#  --========================================================================--
#  This confidential and proprietary software may be used only as
#  authorised by a licensing agreement from ARM Limited
#    (C) COPYRIGHT 2005 ARM Limited
#        ALL RIGHTS RESERVED
#  The entire notice above must be reproduced on all authorised
#  copies and copies may only be made to the extent permitted
#  by a licensing agreement from ARM Limited.
#
#  ----------------------------------------------------------------------------
# 
# LEF OUT API 
# User Name : user 
# Date : Tue Mar  8 17:30:10 2005
# 
VERSION 5.3 ;
NAMESCASESENSITIVE ON ;
BUSBITCHARS "[]" ;
DIVIDERCHAR "/" ;

SITE ARM7TDMI_site
 CLASS core ;
 SIZE 914.85 BY 584.15 ;
END ARM7TDMI_site


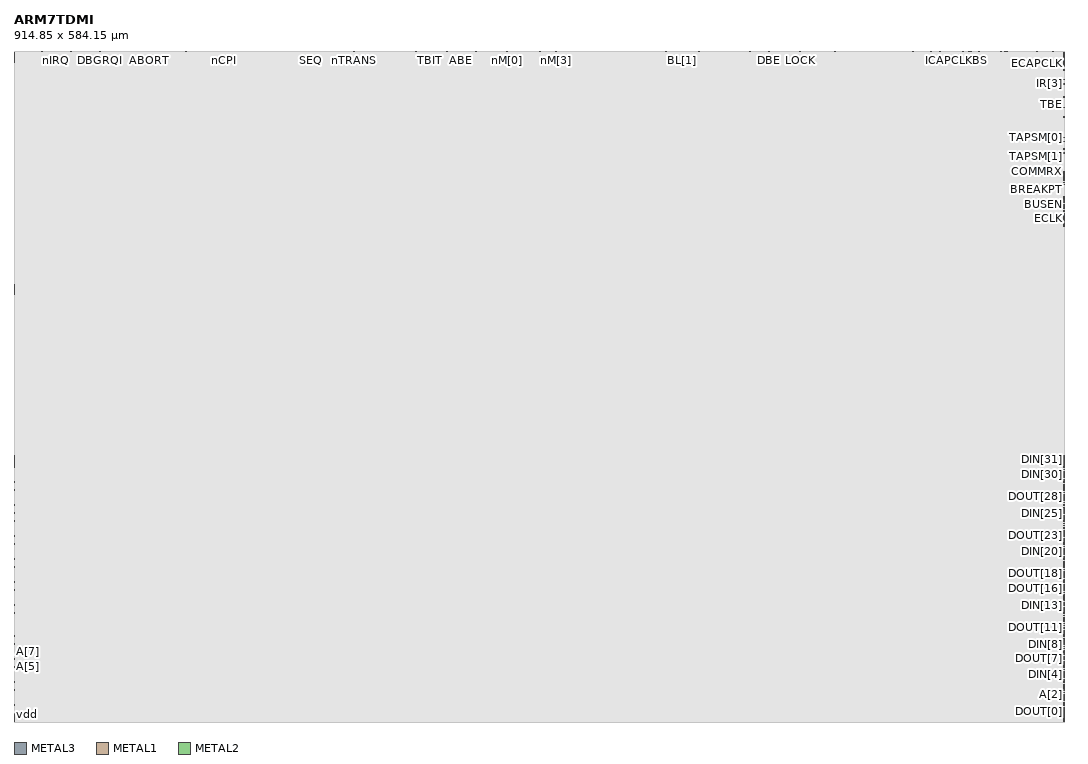
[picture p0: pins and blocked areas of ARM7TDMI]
MACRO ARM7TDMI
 CLASS BLOCK ;
 ORIGIN 0 0 ;
 FOREIGN ARM7TDMI 0.00 0.00 ;
 SYMMETRY X Y R90 ;
 SIZE 914.85 BY 584.15 ;
SITE ARM7TDMI_site ;

 PIN DOUT[25]
 DIRECTION OUTPUT ;
 USE SIGNAL ;
 PORT
 LAYER METAL3 ;
 RECT 914.48 175.98 914.85 176.54 ;
 END
 END DOUT[25]

 PIN A[25]
 DIRECTION OUTPUT ;
 USE SIGNAL ;
 PORT
 LAYER METAL3 ;
 RECT 914.48 177.52 914.85 178.08 ;
 END
 PORT
 LAYER METAL3 ;
 RECT 0 181.82 0.37 182.38 ;
 END
 ANTENNASIZE 0.324 ;
 END A[25]

 PIN D[25]
 DIRECTION INOUT ;
 USE SIGNAL ;
 PORT
 LAYER METAL3 ;
 RECT 914.48 179.48 914.85 180.04 ;
 END
 ANTENNASIZE 2.394 ;
 END D[25]

 PIN DIN[24]
 DIRECTION INPUT ;
 USE SIGNAL ;
 PORT
 LAYER METAL3 ;
 RECT 914.48 174.88 914.85 175.44 ;
 END
 ANTENNASIZE 1.08 ;
 END DIN[24]

 PIN DOUT[24]
 DIRECTION OUTPUT ;
 USE SIGNAL ;
 PORT
 LAYER METAL3 ;
 RECT 914.48 169.28 914.85 169.84 ;
 END
 END DOUT[24]

 PIN A[24]
 DIRECTION OUTPUT ;
 USE SIGNAL ;
 PORT
 LAYER METAL3 ;
 RECT 914.48 170.82 914.85 171.38 ;
 END
 PORT
 LAYER METAL3 ;
 RECT 0 175.12 0.37 175.68 ;
 END
 ANTENNASIZE 0.324 ;
 END A[24]

 PIN D[24]
 DIRECTION INOUT ;
 USE SIGNAL ;
 PORT
 LAYER METAL3 ;
 RECT 914.48 172.78 914.85 173.34 ;
 END
 ANTENNASIZE 2.394 ;
 END D[24]

 PIN DIN[23]
 DIRECTION INPUT ;
 USE SIGNAL ;
 PORT
 LAYER METAL3 ;
 RECT 914.48 168.18 914.85 168.74 ;
 END
 ANTENNASIZE 1.08 ;
 END DIN[23]

 PIN DOUT[23]
 DIRECTION OUTPUT ;
 USE SIGNAL ;
 PORT
 LAYER METAL3 ;
 RECT 914.48 162.58 914.85 163.14 ;
 END
 END DOUT[23]

 PIN A[23]
 DIRECTION OUTPUT ;
 USE SIGNAL ;
 PORT
 LAYER METAL3 ;
 RECT 914.48 164.12 914.85 164.68 ;
 END
 PORT
 LAYER METAL3 ;
 RECT 0 168.42 0.37 168.98 ;
 END
 ANTENNASIZE 0.324 ;
 END A[23]

 PIN D[23]
 DIRECTION INOUT ;
 USE SIGNAL ;
 PORT
 LAYER METAL3 ;
 RECT 914.48 166.08 914.85 166.64 ;
 END
 ANTENNASIZE 2.07 ;
 END D[23]

 PIN DIN[22]
 DIRECTION INPUT ;
 USE SIGNAL ;
 PORT
 LAYER METAL3 ;
 RECT 914.48 161.48 914.85 162.04 ;
 END
 ANTENNASIZE 1.08 ;
 END DIN[22]

 PIN DOUT[22]
 DIRECTION OUTPUT ;
 USE SIGNAL ;
 PORT
 LAYER METAL3 ;
 RECT 914.48 155.88 914.85 156.44 ;
 END
 END DOUT[22]

 PIN A[22]
 DIRECTION OUTPUT ;
 USE SIGNAL ;
 PORT
 LAYER METAL3 ;
 RECT 914.48 157.42 914.85 157.98 ;
 END
 PORT
 LAYER METAL3 ;
 RECT 0 161.72 0.37 162.28 ;
 END
 ANTENNASIZE 0.324 ;
 END A[22]

 PIN D[22]
 DIRECTION INOUT ;
 USE SIGNAL ;
 PORT
 LAYER METAL3 ;
 RECT 914.48 159.38 914.85 159.94 ;
 END
 ANTENNASIZE 2.07 ;
 END D[22]

 PIN DIN[21]
 DIRECTION INPUT ;
 USE SIGNAL ;
 PORT
 LAYER METAL3 ;
 RECT 914.48 154.78 914.85 155.34 ;
 END
 ANTENNASIZE 1.08 ;
 END DIN[21]

 PIN DOUT[21]
 DIRECTION OUTPUT ;
 USE SIGNAL ;
 PORT
 LAYER METAL3 ;
 RECT 914.48 149.18 914.85 149.74 ;
 END
 END DOUT[21]

 PIN A[21]
 DIRECTION OUTPUT ;
 USE SIGNAL ;
 PORT
 LAYER METAL3 ;
 RECT 914.48 150.72 914.85 151.28 ;
 END
 PORT
 LAYER METAL3 ;
 RECT 0 155.02 0.37 155.58 ;
 END
 ANTENNASIZE 0.324 ;
 END A[21]

 PIN D[21]
 DIRECTION INOUT ;
 USE SIGNAL ;
 PORT
 LAYER METAL3 ;
 RECT 914.48 152.68 914.85 153.24 ;
 END
 ANTENNASIZE 2.07 ;
 END D[21]

 PIN DIN[20]
 DIRECTION INPUT ;
 USE SIGNAL ;
 PORT
 LAYER METAL3 ;
 RECT 914.48 148.08 914.85 148.64 ;
 END
 ANTENNASIZE 1.08 ;
 END DIN[20]

 PIN DOUT[20]
 DIRECTION OUTPUT ;
 USE SIGNAL ;
 PORT
 LAYER METAL3 ;
 RECT 914.48 142.48 914.85 143.04 ;
 END
 END DOUT[20]

 PIN A[20]
 DIRECTION OUTPUT ;
 USE SIGNAL ;
 PORT
 LAYER METAL3 ;
 RECT 914.48 144.02 914.85 144.58 ;
 END
 PORT
 LAYER METAL3 ;
 RECT 0 148.32 0.37 148.88 ;
 END
 ANTENNASIZE 0.324 ;
 END A[20]

 PIN D[20]
 DIRECTION INOUT ;
 USE SIGNAL ;
 PORT
 LAYER METAL3 ;
 RECT 914.48 145.98 914.85 146.54 ;
 END
 ANTENNASIZE 2.394 ;
 END D[20]

 PIN DIN[19]
 DIRECTION INPUT ;
 USE SIGNAL ;
 PORT
 LAYER METAL3 ;
 RECT 914.48 141.38 914.85 141.94 ;
 END
 ANTENNASIZE 1.08 ;
 END DIN[19]

 PIN DOUT[18]
 DIRECTION OUTPUT ;
 USE SIGNAL ;
 PORT
 LAYER METAL3 ;
 RECT 914.48 129.08 914.85 129.64 ;
 END
 END DOUT[18]

 PIN ECLK
 DIRECTION OUTPUT ;
 USE SIGNAL ;
 PORT
 LAYER METAL3 ;
 RECT 914.48 445.12 914.85 445.68 ;
 END
 ANTENNASIZE 6.093 ;
 END ECLK

 PIN MCLK
 DIRECTION INPUT ;
 USE SIGNAL ;
 PORT
 LAYER METAL3 ;
 RECT 914.48 441.9 914.85 442.46 ;
 END
 ANTENNASIZE 4.05 ;
 END MCLK

 PIN RSTCLKBS
 DIRECTION OUTPUT ;
 USE SIGNAL ;
 PORT
 LAYER METAL3 ;
 RECT 914.48 442.74 914.85 443.3 ;
 END
 ANTENNASIZE 2.025 ;
 END RSTCLKBS

 PIN vdd
 DIRECTION INOUT ;
 USE POWER ;
 PORT
 LAYER METAL3 ;
 RECT 0 227.8 0.28 231.8 ;
 END
 PORT
 LAYER METAL3 ;
 RECT 914.57 227.8 914.85 231.8 ;
 END
 PORT
 LAYER METAL3 ;
 RECT 0 376.91 0.28 380.89 ;
 END
 PORT
 LAYER METAL3 ;
 RECT 914.57 437 914.85 441 ;
 END
 PORT
 LAYER METAL3 ;
 RECT 914.57 574.96 914.85 578.96 ;
 END
 PORT
 LAYER METAL3 ;
 RECT 0 574.97 0.28 578.95 ;
 END
 PORT
 LAYER METAL1 ;
 RECT 0 0.6 0.28 6.54 ;
 END
 PORT
 LAYER METAL1 ;
 RECT 914.57 0.6 914.85 6.54 ;
 END
 END vdd

 PIN nTRST
 DIRECTION INPUT ;
 USE SIGNAL ;
 PORT
 LAYER METAL3 ;
 RECT 914.48 559.42 914.85 559.98 ;
 END
 ANTENNASIZE 0.99 ;
 END nTRST

 PIN RANGEOUT1
 DIRECTION OUTPUT ;
 USE SIGNAL ;
 PORT
 LAYER METAL3 ;
 RECT 914.48 447.52 914.85 448.08 ;
 END
 END RANGEOUT1

 PIN RANGEOUT0
 DIRECTION OUTPUT ;
 USE SIGNAL ;
 PORT
 LAYER METAL3 ;
 RECT 914.48 449.12 914.85 449.68 ;
 END
 END RANGEOUT0

 PIN BUSEN
 DIRECTION INPUT ;
 USE SIGNAL ;
 PORT
 LAYER METAL3 ;
 RECT 914.48 450.72 914.85 451.28 ;
 END
 ANTENNASIZE 0.522 ;
 END BUSEN

 PIN EXTERN0
 DIRECTION INPUT ;
 USE SIGNAL ;
 PORT
 LAYER METAL3 ;
 RECT 914.48 452.32 914.85 452.88 ;
 END
 ANTENNASIZE 0.522 ;
 END EXTERN0

 PIN DBGACK
 DIRECTION OUTPUT ;
 USE SIGNAL ;
 PORT
 LAYER METAL3 ;
 RECT 914.48 453.92 914.85 454.48 ;
 END
 END DBGACK

 PIN EXTERN1
 DIRECTION INPUT ;
 USE SIGNAL ;
 PORT
 LAYER METAL3 ;
 RECT 914.48 455.52 914.85 456.08 ;
 END
 ANTENNASIZE 0.522 ;
 END EXTERN1

 PIN BREAKPT
 DIRECTION INPUT ;
 USE SIGNAL ;
 PORT
 LAYER METAL3 ;
 RECT 914.48 457.12 914.85 457.68 ;
 END
 ANTENNASIZE 0.522 ;
 END BREAKPT

 PIN CPB
 DIRECTION INPUT ;
 USE SIGNAL ;
 PORT
 LAYER METAL3 ;
 RECT 914.48 469.78 914.85 470.34 ;
 END
 ANTENNASIZE 0.522 ;
 END CPB

 PIN CPA
 DIRECTION INPUT ;
 USE SIGNAL ;
 PORT
 LAYER METAL3 ;
 RECT 914.48 471.38 914.85 471.94 ;
 END
 ANTENNASIZE 0.522 ;
 END CPA

 PIN nENOUTI
 DIRECTION OUTPUT ;
 USE SIGNAL ;
 PORT
 LAYER METAL3 ;
 RECT 914.48 472.98 914.85 473.54 ;
 END
 END nENOUTI

 PIN DBGEN
 DIRECTION INPUT ;
 USE SIGNAL ;
 PORT
 LAYER METAL3 ;
 RECT 914.48 474.58 914.85 475.14 ;
 END
 ANTENNASIZE 0.522 ;
 END DBGEN

 PIN COMMTX
 DIRECTION OUTPUT ;
 USE SIGNAL ;
 PORT
 LAYER METAL3 ;
 RECT 914.48 476.18 914.85 476.74 ;
 END
 END COMMTX

 PIN DBGRQ
 DIRECTION INPUT ;
 USE SIGNAL ;
 PORT
 LAYER METAL3 ;
 RECT 914.48 477.78 914.85 478.34 ;
 END
 ANTENNASIZE 0.522 ;
 END DBGRQ

 PIN COMMRX
 DIRECTION OUTPUT ;
 USE SIGNAL ;
 PORT
 LAYER METAL3 ;
 RECT 914.48 479.38 914.85 479.94 ;
 END
 END COMMRX

 PIN SDINBS
 DIRECTION OUTPUT ;
 USE SIGNAL ;
 PORT
 LAYER METAL3 ;
 RECT 914.48 468.18 914.85 468.74 ;
 END
 ANTENNASIZE 0.558 ;
 END SDINBS

 PIN TAPSM[3]
 DIRECTION OUTPUT ;
 USE SIGNAL ;
 PORT
 LAYER METAL3 ;
 RECT 914.48 495.52 914.85 496.08 ;
 END
 END TAPSM[3]

 PIN TAPSM[1]
 DIRECTION OUTPUT ;
 USE SIGNAL ;
 PORT
 LAYER METAL3 ;
 RECT 914.48 499.12 914.85 499.68 ;
 END
 END TAPSM[1]

 PIN TAPSM[2]
 DIRECTION OUTPUT ;
 USE SIGNAL ;
 PORT
 LAYER METAL3 ;
 RECT 914.48 505.42 914.85 505.98 ;
 END
 END TAPSM[2]

 PIN TAPSM[0]
 DIRECTION OUTPUT ;
 USE SIGNAL ;
 PORT
 LAYER METAL3 ;
 RECT 914.48 509.02 914.85 509.58 ;
 END
 END TAPSM[0]

 PIN HIGHZ
 DIRECTION OUTPUT ;
 USE SIGNAL ;
 PORT
 LAYER METAL3 ;
 RECT 914.48 527.02 914.85 527.58 ;
 END
 END HIGHZ

 PIN nHIGHZ
 DIRECTION OUTPUT ;
 USE SIGNAL ;
 PORT
 LAYER METAL3 ;
 RECT 914.48 535.12 914.85 535.68 ;
 END
 END nHIGHZ

 PIN TBE
 DIRECTION INPUT ;
 USE SIGNAL ;
 PORT
 LAYER METAL3 ;
 RECT 914.48 544.12 914.85 544.68 ;
 END
 ANTENNASIZE 0.468 ;
 END TBE

 PIN IR[3]
 DIRECTION OUTPUT ;
 USE SIGNAL ;
 PORT
 LAYER METAL3 ;
 RECT 914.48 555.82 914.85 556.38 ;
 END
 END IR[3]

 PIN IR[1]
 DIRECTION OUTPUT ;
 USE SIGNAL ;
 PORT
 LAYER METAL3 ;
 RECT 914.48 567.52 914.85 568.08 ;
 END
 END IR[1]

 PIN IR[0]
 DIRECTION OUTPUT ;
 USE SIGNAL ;
 PORT
 LAYER METAL3 ;
 RECT 914.48 572.92 914.85 573.48 ;
 END
 END IR[0]

 PIN IR[2]
 DIRECTION OUTPUT ;
 USE SIGNAL ;
 PORT
 LAYER METAL3 ;
 RECT 914.48 571.12 914.85 571.68 ;
 END
 END IR[2]

 PIN ECAPCLK
 DIRECTION OUTPUT ;
 USE SIGNAL ;
 PORT
 LAYER METAL3 ;
 RECT 914.48 573.82 914.85 574.38 ;
 END
 END ECAPCLK

 PIN vss
 DIRECTION INOUT ;
 USE GROUND ;
 PORT
 LAYER METAL3 ;
 RECT 0 1.7 0.28 7.7 ;
 END
 PORT
 LAYER METAL3 ;
 RECT 914.57 1.7 914.85 7.7 ;
 END
 PORT
 LAYER METAL3 ;
 RECT 0 223.2 0.28 227.2 ;
 END
 PORT
 LAYER METAL3 ;
 RECT 914.57 223.2 914.85 227.2 ;
 END
 PORT
 LAYER METAL3 ;
 RECT 0 372.21 0.28 376.19 ;
 END
 PORT
 LAYER METAL3 ;
 RECT 914.57 432 914.85 436 ;
 END
 PORT
 LAYER METAL3 ;
 RECT 0 579.57 0.28 583.55 ;
 END
 PORT
 LAYER METAL3 ;
 RECT 914.57 579.57 914.85 583.55 ;
 END
 END vss

 PIN DIN[10]
 DIRECTION INPUT ;
 USE SIGNAL ;
 PORT
 LAYER METAL3 ;
 RECT 914.48 81.08 914.85 81.64 ;
 END
 ANTENNASIZE 1.08 ;
 END DIN[10]

 PIN DOUT[10]
 DIRECTION OUTPUT ;
 USE SIGNAL ;
 PORT
 LAYER METAL3 ;
 RECT 914.48 75.48 914.85 76.04 ;
 END
 END DOUT[10]

 PIN D[10]
 DIRECTION INOUT ;
 USE SIGNAL ;
 PORT
 LAYER METAL3 ;
 RECT 914.48 78.98 914.85 79.54 ;
 END
 ANTENNASIZE 2.394 ;
 END D[10]

 PIN DIN[9]
 DIRECTION INPUT ;
 USE SIGNAL ;
 PORT
 LAYER METAL3 ;
 RECT 914.48 74.38 914.85 74.94 ;
 END
 ANTENNASIZE 1.08 ;
 END DIN[9]

 PIN DOUT[9]
 DIRECTION OUTPUT ;
 USE SIGNAL ;
 PORT
 LAYER METAL3 ;
 RECT 914.48 68.78 914.85 69.34 ;
 END
 END DOUT[9]

 PIN D[9]
 DIRECTION INOUT ;
 USE SIGNAL ;
 PORT
 LAYER METAL3 ;
 RECT 914.48 72.28 914.85 72.84 ;
 END
 ANTENNASIZE 2.394 ;
 END D[9]

 PIN DIN[8]
 DIRECTION INPUT ;
 USE SIGNAL ;
 PORT
 LAYER METAL3 ;
 RECT 914.48 67.68 914.85 68.24 ;
 END
 ANTENNASIZE 1.08 ;
 END DIN[8]

 PIN DOUT[8]
 DIRECTION OUTPUT ;
 USE SIGNAL ;
 PORT
 LAYER METAL3 ;
 RECT 914.48 62.08 914.85 62.64 ;
 END
 END DOUT[8]

 PIN D[8]
 DIRECTION INOUT ;
 USE SIGNAL ;
 PORT
 LAYER METAL3 ;
 RECT 914.48 65.58 914.85 66.14 ;
 END
 ANTENNASIZE 2.394 ;
 END D[8]

 PIN DIN[7]
 DIRECTION INPUT ;
 USE SIGNAL ;
 PORT
 LAYER METAL3 ;
 RECT 914.48 60.98 914.85 61.54 ;
 END
 ANTENNASIZE 1.08 ;
 END DIN[7]

 PIN DOUT[7]
 DIRECTION OUTPUT ;
 USE SIGNAL ;
 PORT
 LAYER METAL3 ;
 RECT 914.48 55.38 914.85 55.94 ;
 END
 END DOUT[7]

 PIN D[7]
 DIRECTION INOUT ;
 USE SIGNAL ;
 PORT
 LAYER METAL3 ;
 RECT 914.48 58.88 914.85 59.44 ;
 END
 ANTENNASIZE 2.07 ;
 END D[7]

 PIN DIN[6]
 DIRECTION INPUT ;
 USE SIGNAL ;
 PORT
 LAYER METAL3 ;
 RECT 914.48 54.28 914.85 54.84 ;
 END
 ANTENNASIZE 1.08 ;
 END DIN[6]

 PIN DOUT[4]
 DIRECTION OUTPUT ;
 USE SIGNAL ;
 PORT
 LAYER METAL3 ;
 RECT 914.48 35.28 914.85 35.84 ;
 END
 END DOUT[4]

 PIN DIN[3]
 DIRECTION INPUT ;
 USE SIGNAL ;
 PORT
 LAYER METAL3 ;
 RECT 914.48 34.18 914.85 34.74 ;
 END
 ANTENNASIZE 1.08 ;
 END DIN[3]

 PIN DOUT[3]
 DIRECTION OUTPUT ;
 USE SIGNAL ;
 PORT
 LAYER METAL3 ;
 RECT 914.48 28.58 914.85 29.14 ;
 END
 END DOUT[3]

 PIN DIN[2]
 DIRECTION INPUT ;
 USE SIGNAL ;
 PORT
 LAYER METAL3 ;
 RECT 914.48 27.48 914.85 28.04 ;
 END
 ANTENNASIZE 1.08 ;
 END DIN[2]

 PIN DOUT[5]
 DIRECTION OUTPUT ;
 USE SIGNAL ;
 PORT
 LAYER METAL3 ;
 RECT 914.48 41.98 914.85 42.54 ;
 END
 END DOUT[5]

 PIN DIN[4]
 DIRECTION INPUT ;
 USE SIGNAL ;
 PORT
 LAYER METAL3 ;
 RECT 914.48 40.88 914.85 41.44 ;
 END
 ANTENNASIZE 1.08 ;
 END DIN[4]

 PIN D[4]
 DIRECTION INOUT ;
 USE SIGNAL ;
 PORT
 LAYER METAL3 ;
 RECT 914.48 38.78 914.85 39.34 ;
 END
 ANTENNASIZE 2.394 ;
 END D[4]

 PIN DOUT[6]
 DIRECTION OUTPUT ;
 USE SIGNAL ;
 PORT
 LAYER METAL3 ;
 RECT 914.48 48.68 914.85 49.24 ;
 END
 END DOUT[6]

 PIN DIN[5]
 DIRECTION INPUT ;
 USE SIGNAL ;
 PORT
 LAYER METAL3 ;
 RECT 914.48 47.58 914.85 48.14 ;
 END
 ANTENNASIZE 1.08 ;
 END DIN[5]

 PIN D[5]
 DIRECTION INOUT ;
 USE SIGNAL ;
 PORT
 LAYER METAL3 ;
 RECT 914.48 45.48 914.85 46.04 ;
 END
 ANTENNASIZE 2.07 ;
 END D[5]

 PIN D[6]
 DIRECTION INOUT ;
 USE SIGNAL ;
 PORT
 LAYER METAL3 ;
 RECT 914.48 52.18 914.85 52.74 ;
 END
 ANTENNASIZE 2.07 ;
 END D[6]

 PIN D[3]
 DIRECTION INOUT ;
 USE SIGNAL ;
 PORT
 LAYER METAL3 ;
 RECT 914.48 32.08 914.85 32.64 ;
 END
 ANTENNASIZE 2.07 ;
 END D[3]

 PIN DOUT[2]
 DIRECTION OUTPUT ;
 USE SIGNAL ;
 PORT
 LAYER METAL3 ;
 RECT 914.48 21.88 914.85 22.44 ;
 END
 END DOUT[2]

 PIN DIN[1]
 DIRECTION INPUT ;
 USE SIGNAL ;
 PORT
 LAYER METAL3 ;
 RECT 914.48 20.78 914.85 21.34 ;
 END
 ANTENNASIZE 1.08 ;
 END DIN[1]

 PIN D[2]
 DIRECTION INOUT ;
 USE SIGNAL ;
 PORT
 LAYER METAL3 ;
 RECT 914.48 25.38 914.85 25.94 ;
 END
 ANTENNASIZE 2.07 ;
 END D[2]

 PIN D[1]
 DIRECTION INOUT ;
 USE SIGNAL ;
 PORT
 LAYER METAL3 ;
 RECT 914.48 18.68 914.85 19.24 ;
 END
 ANTENNASIZE 2.07 ;
 END D[1]

 PIN DOUT[0]
 DIRECTION OUTPUT ;
 USE SIGNAL ;
 PORT
 LAYER METAL3 ;
 RECT 914.48 8.48 914.85 9.04 ;
 END
 END DOUT[0]

 PIN DOUT[1]
 DIRECTION OUTPUT ;
 USE SIGNAL ;
 PORT
 LAYER METAL3 ;
 RECT 914.48 15.18 914.85 15.74 ;
 END
 END DOUT[1]

 PIN DIN[0]
 DIRECTION INPUT ;
 USE SIGNAL ;
 PORT
 LAYER METAL3 ;
 RECT 914.48 14.08 914.85 14.64 ;
 END
 ANTENNASIZE 1.08 ;
 END DIN[0]

 PIN D[0]
 DIRECTION INOUT ;
 USE SIGNAL ;
 PORT
 LAYER METAL3 ;
 RECT 914.48 11.98 914.85 12.54 ;
 END
 ANTENNASIZE 2.07 ;
 END D[0]

 PIN A[1]
 DIRECTION OUTPUT ;
 USE SIGNAL ;
 PORT
 LAYER METAL3 ;
 RECT 914.48 16.72 914.85 17.28 ;
 END
 PORT
 LAYER METAL3 ;
 RECT 0 21.02 0.37 21.58 ;
 END
 ANTENNASIZE 1.161 ;
 END A[1]

 PIN A[0]
 DIRECTION OUTPUT ;
 USE SIGNAL ;
 PORT
 LAYER METAL3 ;
 RECT 914.48 10.02 914.85 10.58 ;
 END
 PORT
 LAYER METAL3 ;
 RECT 0 14.32 0.37 14.88 ;
 END
 ANTENNASIZE 0.324 ;
 END A[0]

 PIN A[5]
 DIRECTION OUTPUT ;
 USE SIGNAL ;
 PORT
 LAYER METAL3 ;
 RECT 914.48 43.52 914.85 44.08 ;
 END
 PORT
 LAYER METAL3 ;
 RECT 0 47.82 0.37 48.38 ;
 END
 ANTENNASIZE 0.324 ;
 END A[5]

 PIN A[4]
 DIRECTION OUTPUT ;
 USE SIGNAL ;
 PORT
 LAYER METAL3 ;
 RECT 914.48 36.82 914.85 37.38 ;
 END
 PORT
 LAYER METAL3 ;
 RECT 0 41.12 0.37 41.68 ;
 END
 ANTENNASIZE 0.324 ;
 END A[4]

 PIN A[3]
 DIRECTION OUTPUT ;
 USE SIGNAL ;
 PORT
 LAYER METAL3 ;
 RECT 914.48 30.12 914.85 30.68 ;
 END
 PORT
 LAYER METAL3 ;
 RECT 0 34.42 0.37 34.98 ;
 END
 ANTENNASIZE 0.324 ;
 END A[3]

 PIN A[8]
 DIRECTION OUTPUT ;
 USE SIGNAL ;
 PORT
 LAYER METAL3 ;
 RECT 914.48 63.62 914.85 64.18 ;
 END
 PORT
 LAYER METAL3 ;
 RECT 0 67.92 0.37 68.48 ;
 END
 ANTENNASIZE 0.324 ;
 END A[8]

 PIN A[7]
 DIRECTION OUTPUT ;
 USE SIGNAL ;
 PORT
 LAYER METAL3 ;
 RECT 914.48 56.92 914.85 57.48 ;
 END
 PORT
 LAYER METAL3 ;
 RECT 0 61.22 0.37 61.78 ;
 END
 ANTENNASIZE 0.324 ;
 END A[7]

 PIN A[6]
 DIRECTION OUTPUT ;
 USE SIGNAL ;
 PORT
 LAYER METAL3 ;
 RECT 914.48 50.22 914.85 50.78 ;
 END
 PORT
 LAYER METAL3 ;
 RECT 0 54.52 0.37 55.08 ;
 END
 ANTENNASIZE 0.324 ;
 END A[6]

 PIN A[10]
 DIRECTION OUTPUT ;
 USE SIGNAL ;
 PORT
 LAYER METAL3 ;
 RECT 914.48 77.02 914.85 77.58 ;
 END
 PORT
 LAYER METAL3 ;
 RECT 0 81.32 0.37 81.88 ;
 END
 ANTENNASIZE 0.324 ;
 END A[10]

 PIN A[9]
 DIRECTION OUTPUT ;
 USE SIGNAL ;
 PORT
 LAYER METAL3 ;
 RECT 914.48 70.32 914.85 70.88 ;
 END
 PORT
 LAYER METAL3 ;
 RECT 0 74.62 0.37 75.18 ;
 END
 ANTENNASIZE 0.324 ;
 END A[9]

 PIN A[2]
 DIRECTION OUTPUT ;
 USE SIGNAL ;
 PORT
 LAYER METAL3 ;
 RECT 914.48 23.42 914.85 23.98 ;
 END
 PORT
 LAYER METAL3 ;
 RECT 0 27.72 0.37 28.28 ;
 END
 ANTENNASIZE 0.324 ;
 END A[2]

 PIN A[13]
 DIRECTION OUTPUT ;
 USE SIGNAL ;
 PORT
 LAYER METAL3 ;
 RECT 914.48 97.12 914.85 97.68 ;
 END
 PORT
 LAYER METAL3 ;
 RECT 0 101.42 0.37 101.98 ;
 END
 ANTENNASIZE 0.324 ;
 END A[13]

 PIN A[12]
 DIRECTION OUTPUT ;
 USE SIGNAL ;
 PORT
 LAYER METAL3 ;
 RECT 914.48 90.42 914.85 90.98 ;
 END
 PORT
 LAYER METAL3 ;
 RECT 0 94.72 0.37 95.28 ;
 END
 ANTENNASIZE 0.324 ;
 END A[12]

 PIN A[11]
 DIRECTION OUTPUT ;
 USE SIGNAL ;
 PORT
 LAYER METAL3 ;
 RECT 914.48 83.72 914.85 84.28 ;
 END
 PORT
 LAYER METAL3 ;
 RECT 0 88.02 0.37 88.58 ;
 END
 ANTENNASIZE 0.324 ;
 END A[11]

 PIN A[15]
 DIRECTION OUTPUT ;
 USE SIGNAL ;
 PORT
 LAYER METAL3 ;
 RECT 914.48 110.52 914.85 111.08 ;
 END
 PORT
 LAYER METAL3 ;
 RECT 0 114.82 0.37 115.38 ;
 END
 ANTENNASIZE 0.324 ;
 END A[15]

 PIN A[14]
 DIRECTION OUTPUT ;
 USE SIGNAL ;
 PORT
 LAYER METAL3 ;
 RECT 914.48 103.82 914.85 104.38 ;
 END
 PORT
 LAYER METAL3 ;
 RECT 0 108.12 0.37 108.68 ;
 END
 ANTENNASIZE 0.324 ;
 END A[14]

 PIN A[18]
 DIRECTION OUTPUT ;
 USE SIGNAL ;
 PORT
 LAYER METAL3 ;
 RECT 914.48 130.62 914.85 131.18 ;
 END
 PORT
 LAYER METAL3 ;
 RECT 0 134.92 0.37 135.48 ;
 END
 ANTENNASIZE 0.324 ;
 END A[18]

 PIN A[17]
 DIRECTION OUTPUT ;
 USE SIGNAL ;
 PORT
 LAYER METAL3 ;
 RECT 914.48 123.92 914.85 124.48 ;
 END
 PORT
 LAYER METAL3 ;
 RECT 0 128.22 0.37 128.78 ;
 END
 ANTENNASIZE 0.324 ;
 END A[17]

 PIN A[16]
 DIRECTION OUTPUT ;
 USE SIGNAL ;
 PORT
 LAYER METAL3 ;
 RECT 914.48 117.22 914.85 117.78 ;
 END
 PORT
 LAYER METAL3 ;
 RECT 0 121.52 0.37 122.08 ;
 END
 ANTENNASIZE 0.324 ;
 END A[16]

 PIN A[19]
 DIRECTION OUTPUT ;
 USE SIGNAL ;
 PORT
 LAYER METAL3 ;
 RECT 914.48 137.32 914.85 137.88 ;
 END
 PORT
 LAYER METAL3 ;
 RECT 0 141.62 0.37 142.18 ;
 END
 ANTENNASIZE 0.324 ;
 END A[19]

 PIN DIN[31]
 DIRECTION INPUT ;
 USE SIGNAL ;
 PORT
 LAYER METAL3 ;
 RECT 914.48 221.78 914.85 222.34 ;
 END
 ANTENNASIZE 1.08 ;
 END DIN[31]

 PIN DOUT[31]
 DIRECTION OUTPUT ;
 USE SIGNAL ;
 PORT
 LAYER METAL3 ;
 RECT 914.48 216.18 914.85 216.74 ;
 END
 END DOUT[31]

 PIN A[31]
 DIRECTION OUTPUT ;
 USE SIGNAL ;
 PORT
 LAYER METAL3 ;
 RECT 914.48 217.72 914.85 218.28 ;
 END
 PORT
 LAYER METAL3 ;
 RECT 0 222.02 0.37 222.58 ;
 END
 ANTENNASIZE 0.324 ;
 END A[31]

 PIN D[31]
 DIRECTION INOUT ;
 USE SIGNAL ;
 PORT
 LAYER METAL3 ;
 RECT 914.48 219.68 914.85 220.24 ;
 END
 ANTENNASIZE 2.07 ;
 END D[31]

 PIN DIN[30]
 DIRECTION INPUT ;
 USE SIGNAL ;
 PORT
 LAYER METAL3 ;
 RECT 914.48 215.08 914.85 215.64 ;
 END
 ANTENNASIZE 1.08 ;
 END DIN[30]

 PIN DOUT[30]
 DIRECTION OUTPUT ;
 USE SIGNAL ;
 PORT
 LAYER METAL3 ;
 RECT 914.48 209.48 914.85 210.04 ;
 END
 END DOUT[30]

 PIN A[30]
 DIRECTION OUTPUT ;
 USE SIGNAL ;
 PORT
 LAYER METAL3 ;
 RECT 914.48 211.02 914.85 211.58 ;
 END
 PORT
 LAYER METAL3 ;
 RECT 0 215.32 0.37 215.88 ;
 END
 ANTENNASIZE 0.324 ;
 END A[30]

 PIN D[30]
 DIRECTION INOUT ;
 USE SIGNAL ;
 PORT
 LAYER METAL3 ;
 RECT 914.48 212.98 914.85 213.54 ;
 END
 ANTENNASIZE 2.07 ;
 END D[30]

 PIN DIN[29]
 DIRECTION INPUT ;
 USE SIGNAL ;
 PORT
 LAYER METAL3 ;
 RECT 914.48 208.38 914.85 208.94 ;
 END
 ANTENNASIZE 1.08 ;
 END DIN[29]

 PIN D[29]
 DIRECTION INOUT ;
 USE SIGNAL ;
 PORT
 LAYER METAL3 ;
 RECT 914.48 206.28 914.85 206.84 ;
 END
 ANTENNASIZE 2.07 ;
 END D[29]

 PIN DOUT[29]
 DIRECTION OUTPUT ;
 USE SIGNAL ;
 PORT
 LAYER METAL3 ;
 RECT 914.48 202.78 914.85 203.34 ;
 END
 END DOUT[29]

 PIN A[29]
 DIRECTION OUTPUT ;
 USE SIGNAL ;
 PORT
 LAYER METAL3 ;
 RECT 914.48 204.32 914.85 204.88 ;
 END
 PORT
 LAYER METAL3 ;
 RECT 0 208.62 0.37 209.18 ;
 END
 ANTENNASIZE 0.324 ;
 END A[29]

 PIN DIN[28]
 DIRECTION INPUT ;
 USE SIGNAL ;
 PORT
 LAYER METAL3 ;
 RECT 914.48 201.68 914.85 202.24 ;
 END
 ANTENNASIZE 1.08 ;
 END DIN[28]

 PIN DOUT[28]
 DIRECTION OUTPUT ;
 USE SIGNAL ;
 PORT
 LAYER METAL3 ;
 RECT 914.48 196.08 914.85 196.64 ;
 END
 END DOUT[28]

 PIN A[28]
 DIRECTION OUTPUT ;
 USE SIGNAL ;
 PORT
 LAYER METAL3 ;
 RECT 914.48 197.62 914.85 198.18 ;
 END
 PORT
 LAYER METAL3 ;
 RECT 0 201.92 0.37 202.48 ;
 END
 ANTENNASIZE 0.324 ;
 END A[28]

 PIN D[28]
 DIRECTION INOUT ;
 USE SIGNAL ;
 PORT
 LAYER METAL3 ;
 RECT 914.48 199.58 914.85 200.14 ;
 END
 ANTENNASIZE 2.07 ;
 END D[28]

 PIN DIN[27]
 DIRECTION INPUT ;
 USE SIGNAL ;
 PORT
 LAYER METAL3 ;
 RECT 914.48 194.98 914.85 195.54 ;
 END
 ANTENNASIZE 1.08 ;
 END DIN[27]

 PIN DOUT[27]
 DIRECTION OUTPUT ;
 USE SIGNAL ;
 PORT
 LAYER METAL3 ;
 RECT 914.48 189.38 914.85 189.94 ;
 END
 END DOUT[27]

 PIN A[27]
 DIRECTION OUTPUT ;
 USE SIGNAL ;
 PORT
 LAYER METAL3 ;
 RECT 914.48 190.92 914.85 191.48 ;
 END
 PORT
 LAYER METAL3 ;
 RECT 0 195.22 0.37 195.78 ;
 END
 ANTENNASIZE 0.324 ;
 END A[27]

 PIN D[27]
 DIRECTION INOUT ;
 USE SIGNAL ;
 PORT
 LAYER METAL3 ;
 RECT 914.48 192.88 914.85 193.44 ;
 END
 ANTENNASIZE 2.394 ;
 END D[27]

 PIN DIN[26]
 DIRECTION INPUT ;
 USE SIGNAL ;
 PORT
 LAYER METAL3 ;
 RECT 914.48 188.28 914.85 188.84 ;
 END
 ANTENNASIZE 1.08 ;
 END DIN[26]

 PIN DOUT[26]
 DIRECTION OUTPUT ;
 USE SIGNAL ;
 PORT
 LAYER METAL3 ;
 RECT 914.48 182.68 914.85 183.24 ;
 END
 END DOUT[26]

 PIN A[26]
 DIRECTION OUTPUT ;
 USE SIGNAL ;
 PORT
 LAYER METAL3 ;
 RECT 914.48 184.22 914.85 184.78 ;
 END
 PORT
 LAYER METAL3 ;
 RECT 0 188.52 0.37 189.08 ;
 END
 ANTENNASIZE 0.324 ;
 END A[26]

 PIN D[26]
 DIRECTION INOUT ;
 USE SIGNAL ;
 PORT
 LAYER METAL3 ;
 RECT 914.48 186.18 914.85 186.74 ;
 END
 ANTENNASIZE 2.394 ;
 END D[26]

 PIN DIN[25]
 DIRECTION INPUT ;
 USE SIGNAL ;
 PORT
 LAYER METAL3 ;
 RECT 914.48 181.58 914.85 182.14 ;
 END
 ANTENNASIZE 1.08 ;
 END DIN[25]

 PIN nWAIT
 DIRECTION INPUT ;
 USE SIGNAL ;
 PORT
 LAYER METAL2 ;
 RECT 349.83 583.78 350.39 584.15 ;
 END
 ANTENNASIZE 0.522 ;
 END nWAIT

 PIN nMREQ
 DIRECTION OUTPUT ;
 USE SIGNAL ;
 PORT
 LAYER METAL2 ;
 RECT 233.63 583.78 234.19 584.15 ;
 END
 ANTENNASIZE 1.026 ;
 END nMREQ

 PIN TBIT
 DIRECTION OUTPUT ;
 USE SIGNAL ;
 PORT
 LAYER METAL2 ;
 RECT 362.49 583.78 363.05 584.15 ;
 END
 ANTENNASIZE 0.504 ;
 END TBIT

 PIN APE
 DIRECTION INPUT ;
 USE SIGNAL ;
 PORT
 LAYER METAL2 ;
 RECT 376.83 583.78 377.39 584.15 ;
 END
 ANTENNASIZE 0.522 ;
 END APE

 PIN ABE
 DIRECTION INPUT ;
 USE SIGNAL ;
 PORT
 LAYER METAL2 ;
 RECT 389.53 583.78 390.09 584.15 ;
 END
 ANTENNASIZE 0.522 ;
 END ABE

 PIN ALE
 DIRECTION INPUT ;
 USE SIGNAL ;
 PORT
 LAYER METAL2 ;
 RECT 402.23 583.78 402.79 584.15 ;
 END
 ANTENNASIZE 0.522 ;
 END ALE

 PIN nEXEC
 DIRECTION OUTPUT ;
 USE SIGNAL ;
 PORT
 LAYER METAL2 ;
 RECT 414.89 583.78 415.45 584.15 ;
 END
 END nEXEC

 PIN nM[0]
 DIRECTION OUTPUT ;
 USE SIGNAL ;
 PORT
 LAYER METAL2 ;
 RECT 429.19 583.78 429.75 584.15 ;
 END
 END nM[0]

 PIN nM[1]
 DIRECTION OUTPUT ;
 USE SIGNAL ;
 PORT
 LAYER METAL2 ;
 RECT 443.49 583.78 444.05 584.15 ;
 END
 END nM[1]

 PIN nM[2]
 DIRECTION OUTPUT ;
 USE SIGNAL ;
 PORT
 LAYER METAL2 ;
 RECT 457.79 583.78 458.35 584.15 ;
 END
 END nM[2]

 PIN nM[3]
 DIRECTION OUTPUT ;
 USE SIGNAL ;
 PORT
 LAYER METAL2 ;
 RECT 472.09 583.78 472.65 584.15 ;
 END
 END nM[3]

 PIN nM[4]
 DIRECTION OUTPUT ;
 USE SIGNAL ;
 PORT
 LAYER METAL2 ;
 RECT 486.39 583.78 486.95 584.15 ;
 END
 END nM[4]

 PIN nENIN
 DIRECTION INPUT ;
 USE SIGNAL ;
 PORT
 LAYER METAL2 ;
 RECT 715.09 583.78 715.65 584.15 ;
 END
 ANTENNASIZE 0.522 ;
 END nENIN

 PIN LOCK
 DIRECTION OUTPUT ;
 USE SIGNAL ;
 PORT
 LAYER METAL2 ;
 RECT 684.69 583.78 685.25 584.15 ;
 END
 END LOCK

 PIN BIGEND
 DIRECTION INPUT ;
 USE SIGNAL ;
 PORT
 LAYER METAL2 ;
 RECT 670.03 583.78 670.59 584.15 ;
 END
 ANTENNASIZE 0.522 ;
 END BIGEND

 PIN DBE
 DIRECTION INPUT ;
 USE SIGNAL ;
 PORT
 LAYER METAL2 ;
 RECT 657.33 583.78 657.89 584.15 ;
 END
 ANTENNASIZE 0.522 ;
 END DBE

 PIN MAS[0]
 DIRECTION OUTPUT ;
 USE SIGNAL ;
 PORT
 LAYER METAL2 ;
 RECT 641.23 583.78 641.79 584.15 ;
 END
 ANTENNASIZE 1.044 ;
 END MAS[0]

 PIN MAS[1]
 DIRECTION OUTPUT ;
 USE SIGNAL ;
 PORT
 LAYER METAL2 ;
 RECT 611.03 583.78 611.59 584.15 ;
 END
 ANTENNASIZE 1.026 ;
 END MAS[1]

 PIN BL[0]
 DIRECTION INPUT ;
 USE SIGNAL ;
 PORT
 LAYER METAL2 ;
 RECT 596.39 583.78 596.95 584.15 ;
 END
 ANTENNASIZE 0.522 ;
 END BL[0]

 PIN BL[1]
 DIRECTION INPUT ;
 USE SIGNAL ;
 PORT
 LAYER METAL2 ;
 RECT 582.09 583.78 582.65 584.15 ;
 END
 ANTENNASIZE 0.522 ;
 END BL[1]

 PIN BL[2]
 DIRECTION INPUT ;
 USE SIGNAL ;
 PORT
 LAYER METAL2 ;
 RECT 567.79 583.78 568.35 584.15 ;
 END
 ANTENNASIZE 0.522 ;
 END BL[2]

 PIN BL[3]
 DIRECTION INPUT ;
 USE SIGNAL ;
 PORT
 LAYER METAL2 ;
 RECT 553.49 583.78 554.05 584.15 ;
 END
 ANTENNASIZE 0.522 ;
 END BL[3]

 PIN nCPI
 DIRECTION OUTPUT ;
 USE SIGNAL ;
 PORT
 LAYER METAL2 ;
 RECT 182.39 583.78 182.95 584.15 ;
 END
 ANTENNASIZE 0.522 ;
 END nCPI

 PIN nOPC
 DIRECTION OUTPUT ;
 USE SIGNAL ;
 PORT
 LAYER METAL2 ;
 RECT 149.63 583.78 150.19 584.15 ;
 END
 ANTENNASIZE 2.07 ;
 END nOPC

 PIN ABORT
 DIRECTION INPUT ;
 USE SIGNAL ;
 PORT
 LAYER METAL2 ;
 RECT 117.63 583.78 118.19 584.15 ;
 END
 ANTENNASIZE 0.522 ;
 END ABORT

 PIN nRW
 DIRECTION OUTPUT ;
 USE SIGNAL ;
 PORT
 LAYER METAL2 ;
 RECT 102.99 583.78 103.55 584.15 ;
 END
 ANTENNASIZE 0.522 ;
 END nRW

 PIN DBGRQI
 DIRECTION OUTPUT ;
 USE SIGNAL ;
 PORT
 LAYER METAL2 ;
 RECT 74.73 583.78 75.29 584.15 ;
 END
 ANTENNASIZE 0.522 ;
 END DBGRQI

 PIN ISYNC
 DIRECTION INPUT ;
 USE SIGNAL ;
 PORT
 LAYER METAL2 ;
 RECT 62.03 583.78 62.59 584.15 ;
 END
 ANTENNASIZE 0.522 ;
 END ISYNC

 PIN nRESET
 DIRECTION INPUT ;
 USE SIGNAL ;
 PORT
 LAYER METAL2 ;
 RECT 49.33 583.77 49.89 584.15 ;
 END
 ANTENNASIZE 1.953 ;
 END nRESET

 PIN nIRQ
 DIRECTION INPUT ;
 USE SIGNAL ;
 PORT
 LAYER METAL2 ;
 RECT 36.63 583.78 37.19 584.15 ;
 END
 ANTENNASIZE 0.522 ;
 END nIRQ

 PIN nFIQ
 DIRECTION INPUT ;
 USE SIGNAL ;
 PORT
 LAYER METAL2 ;
 RECT 23.93 583.78 24.49 584.15 ;
 END
 ANTENNASIZE 0.522 ;
 END nFIQ

 PIN nTRANS
 DIRECTION OUTPUT ;
 USE SIGNAL ;
 PORT
 LAYER METAL2 ;
 RECT 295.79 583.78 296.35 584.15 ;
 END
 ANTENNASIZE 0.522 ;
 END nTRANS

 PIN SEQ
 DIRECTION OUTPUT ;
 USE SIGNAL ;
 PORT
 LAYER METAL2 ;
 RECT 258.79 583.78 259.35 584.15 ;
 END
 END SEQ

 PIN nENOUT
 DIRECTION OUTPUT ;
 USE SIGNAL ;
 PORT
 LAYER METAL2 ;
 RECT 700.73 583.78 701.29 584.15 ;
 END
 ANTENNASIZE 1.26 ;
 END nENOUT

 PIN BUSDIS
 DIRECTION OUTPUT ;
 USE SIGNAL ;
 PORT
 LAYER METAL2 ;
 RECT 783.18 583.78 783.74 584.15 ;
 END
 END BUSDIS

 PIN TCK
 DIRECTION INPUT ;
 USE SIGNAL ;
 PORT
 LAYER METAL2 ;
 RECT 833.58 583.78 834.14 584.15 ;
 END
 ANTENNASIZE 0.522 ;
 END TCK

 PIN SDOUTBS
 DIRECTION INPUT ;
 USE SIGNAL ;
 PORT
 LAYER METAL2 ;
 RECT 816.48 583.78 817.04 584.15 ;
 END
 ANTENNASIZE 0.522 ;
 END SDOUTBS

 PIN ICAPCLKBS
 DIRECTION OUTPUT ;
 USE SIGNAL ;
 PORT
 LAYER METAL2 ;
 RECT 820.98 583.78 821.54 584.15 ;
 END
 END ICAPCLKBS

 PIN ECAPCLKBS
 DIRECTION OUTPUT ;
 USE SIGNAL ;
 PORT
 LAYER METAL2 ;
 RECT 826.38 583.78 826.94 584.15 ;
 END
 END ECAPCLKBS

 PIN PCLKBS
 DIRECTION OUTPUT ;
 USE SIGNAL ;
 PORT
 LAYER METAL2 ;
 RECT 794.88 583.78 795.44 584.15 ;
 END
 END PCLKBS

 PIN SHCLKBS
 DIRECTION OUTPUT ;
 USE SIGNAL ;
 PORT
 LAYER METAL2 ;
 RECT 789.48 583.78 790.04 584.15 ;
 END
 END SHCLKBS

 PIN TCK1
 DIRECTION OUTPUT ;
 USE SIGNAL ;
 PORT
 LAYER METAL2 ;
 RECT 850.68 583.78 851.24 584.15 ;
 END
 END TCK1

 PIN DRIVEBS
 DIRECTION OUTPUT ;
 USE SIGNAL ;
 PORT
 LAYER METAL2 ;
 RECT 831.78 583.78 832.34 584.15 ;
 END
 END DRIVEBS

 PIN SHCLK2BS
 DIRECTION OUTPUT ;
 USE SIGNAL ;
 PORT
 LAYER METAL2 ;
 RECT 806.58 583.78 807.14 584.15 ;
 END
 END SHCLK2BS

 PIN TMS
 DIRECTION INPUT ;
 USE SIGNAL ;
 PORT
 LAYER METAL2 ;
 RECT 865.08 583.78 865.64 584.15 ;
 END
 ANTENNASIZE 0.522 ;
 END TMS

 PIN TCK2
 DIRECTION OUTPUT ;
 USE SIGNAL ;
 PORT
 LAYER METAL2 ;
 RECT 891.18 583.78 891.74 584.15 ;
 END
 END TCK2

 PIN SCREG[3]
 DIRECTION OUTPUT ;
 USE SIGNAL ;
 PORT
 LAYER METAL2 ;
 RECT 871.38 583.78 871.94 584.15 ;
 END
 END SCREG[3]

 PIN SCREG[2]
 DIRECTION OUTPUT ;
 USE SIGNAL ;
 PORT
 LAYER METAL2 ;
 RECT 859.68 583.78 860.24 584.15 ;
 END
 END SCREG[2]

 PIN SCREG[1]
 DIRECTION OUTPUT ;
 USE SIGNAL ;
 PORT
 LAYER METAL2 ;
 RECT 863.28 583.78 863.84 584.15 ;
 END
 END SCREG[1]

 PIN SCREG[0]
 DIRECTION OUTPUT ;
 USE SIGNAL ;
 PORT
 LAYER METAL2 ;
 RECT 874.98 583.78 875.54 584.15 ;
 END
 END SCREG[0]

 PIN nTDOEN
 DIRECTION OUTPUT ;
 USE SIGNAL ;
 PORT
 LAYER METAL2 ;
 RECT 798.48 583.78 799.04 584.15 ;
 END
 END nTDOEN

 PIN TDO
 DIRECTION OUTPUT ;
 USE SIGNAL ;
 PORT
 LAYER METAL2 ;
 RECT 840.78 583.78 841.34 584.15 ;
 END
 END TDO

 PIN TDI
 DIRECTION INPUT ;
 USE SIGNAL ;
 PORT
 LAYER METAL2 ;
 RECT 905.08 583.78 905.64 584.15 ;
 END
 ANTENNASIZE 0.522 ;
 END TDI

 PIN DIN[17]
 DIRECTION INPUT ;
 USE SIGNAL ;
 PORT
 LAYER METAL3 ;
 RECT 914.48 127.98 914.85 128.54 ;
 END
 ANTENNASIZE 1.08 ;
 END DIN[17]

 PIN DOUT[17]
 DIRECTION OUTPUT ;
 USE SIGNAL ;
 PORT
 LAYER METAL3 ;
 RECT 914.48 122.38 914.85 122.94 ;
 END
 END DOUT[17]

 PIN D[17]
 DIRECTION INOUT ;
 USE SIGNAL ;
 PORT
 LAYER METAL3 ;
 RECT 914.48 125.88 914.85 126.44 ;
 END
 ANTENNASIZE 2.07 ;
 END D[17]

 PIN DIN[16]
 DIRECTION INPUT ;
 USE SIGNAL ;
 PORT
 LAYER METAL3 ;
 RECT 914.48 121.28 914.85 121.84 ;
 END
 ANTENNASIZE 1.08 ;
 END DIN[16]

 PIN DOUT[16]
 DIRECTION OUTPUT ;
 USE SIGNAL ;
 PORT
 LAYER METAL3 ;
 RECT 914.48 115.68 914.85 116.24 ;
 END
 END DOUT[16]

 PIN D[16]
 DIRECTION INOUT ;
 USE SIGNAL ;
 PORT
 LAYER METAL3 ;
 RECT 914.48 119.18 914.85 119.74 ;
 END
 ANTENNASIZE 2.394 ;
 END D[16]

 PIN DIN[15]
 DIRECTION INPUT ;
 USE SIGNAL ;
 PORT
 LAYER METAL3 ;
 RECT 914.48 114.58 914.85 115.14 ;
 END
 ANTENNASIZE 1.08 ;
 END DIN[15]

 PIN DOUT[15]
 DIRECTION OUTPUT ;
 USE SIGNAL ;
 PORT
 LAYER METAL3 ;
 RECT 914.48 108.98 914.85 109.54 ;
 END
 END DOUT[15]

 PIN D[15]
 DIRECTION INOUT ;
 USE SIGNAL ;
 PORT
 LAYER METAL3 ;
 RECT 914.48 112.48 914.85 113.04 ;
 END
 ANTENNASIZE 2.07 ;
 END D[15]

 PIN DIN[14]
 DIRECTION INPUT ;
 USE SIGNAL ;
 PORT
 LAYER METAL3 ;
 RECT 914.48 107.88 914.85 108.44 ;
 END
 ANTENNASIZE 1.08 ;
 END DIN[14]

 PIN DOUT[19]
 DIRECTION OUTPUT ;
 USE SIGNAL ;
 PORT
 LAYER METAL3 ;
 RECT 914.48 135.78 914.85 136.34 ;
 END
 END DOUT[19]

 PIN D[19]
 DIRECTION INOUT ;
 USE SIGNAL ;
 PORT
 LAYER METAL3 ;
 RECT 914.48 139.28 914.85 139.84 ;
 END
 ANTENNASIZE 2.07 ;
 END D[19]

 PIN DIN[18]
 DIRECTION INPUT ;
 USE SIGNAL ;
 PORT
 LAYER METAL3 ;
 RECT 914.48 134.68 914.85 135.24 ;
 END
 ANTENNASIZE 1.08 ;
 END DIN[18]

 PIN D[18]
 DIRECTION INOUT ;
 USE SIGNAL ;
 PORT
 LAYER METAL3 ;
 RECT 914.48 132.58 914.85 133.14 ;
 END
 ANTENNASIZE 2.07 ;
 END D[18]

 PIN DOUT[14]
 DIRECTION OUTPUT ;
 USE SIGNAL ;
 PORT
 LAYER METAL3 ;
 RECT 914.48 102.28 914.85 102.84 ;
 END
 END DOUT[14]

 PIN D[14]
 DIRECTION INOUT ;
 USE SIGNAL ;
 PORT
 LAYER METAL3 ;
 RECT 914.48 105.78 914.85 106.34 ;
 END
 ANTENNASIZE 2.07 ;
 END D[14]

 PIN DIN[13]
 DIRECTION INPUT ;
 USE SIGNAL ;
 PORT
 LAYER METAL3 ;
 RECT 914.48 101.18 914.85 101.74 ;
 END
 ANTENNASIZE 1.08 ;
 END DIN[13]

 PIN D[13]
 DIRECTION INOUT ;
 USE SIGNAL ;
 PORT
 LAYER METAL3 ;
 RECT 914.48 99.08 914.85 99.64 ;
 END
 ANTENNASIZE 2.07 ;
 END D[13]

 PIN DOUT[13]
 DIRECTION OUTPUT ;
 USE SIGNAL ;
 PORT
 LAYER METAL3 ;
 RECT 914.48 95.58 914.85 96.14 ;
 END
 END DOUT[13]

 PIN DIN[12]
 DIRECTION INPUT ;
 USE SIGNAL ;
 PORT
 LAYER METAL3 ;
 RECT 914.48 94.48 914.85 95.04 ;
 END
 ANTENNASIZE 1.08 ;
 END DIN[12]

 PIN DOUT[12]
 DIRECTION OUTPUT ;
 USE SIGNAL ;
 PORT
 LAYER METAL3 ;
 RECT 914.48 88.88 914.85 89.44 ;
 END
 END DOUT[12]

 PIN D[12]
 DIRECTION INOUT ;
 USE SIGNAL ;
 PORT
 LAYER METAL3 ;
 RECT 914.48 92.38 914.85 92.94 ;
 END
 ANTENNASIZE 2.07 ;
 END D[12]

 PIN DIN[11]
 DIRECTION INPUT ;
 USE SIGNAL ;
 PORT
 LAYER METAL3 ;
 RECT 914.48 87.78 914.85 88.34 ;
 END
 ANTENNASIZE 1.08 ;
 END DIN[11]

 PIN DOUT[11]
 DIRECTION OUTPUT ;
 USE SIGNAL ;
 PORT
 LAYER METAL3 ;
 RECT 914.48 82.18 914.85 82.74 ;
 END
 END DOUT[11]

 PIN D[11]
 DIRECTION INOUT ;
 USE SIGNAL ;
 PORT
 LAYER METAL3 ;
 RECT 914.48 85.68 914.85 86.24 ;
 END
 ANTENNASIZE 2.394 ;
 END D[11]

 OBS
 LAYER POLY1 ;
 RECT 0 0 914.85 584.15 ;
 LAYER METAL1 ;
 RECT 0.88 0 913.97 17.14 ;
 RECT 0 7.14 914.85 584.15 ;
 LAYER METAL2 ;
 RECT 150.79 583.18 181.79 584.15 ;
 RECT 118.79 583.18 149.03 584.15 ;
 RECT 104.15 583.18 117.03 584.15 ;
 RECT 75.89 583.18 102.39 584.15 ;
 RECT 63.19 583.18 74.13 584.15 ;
 RECT 50.49 583.18 61.43 584.15 ;
 RECT 50.49 583.17 914.85 583.18 ;
 RECT 37.79 583.18 48.73 584.15 ;
 RECT 25.09 583.18 36.03 584.15 ;
 RECT 0 583.18 23.33 584.15 ;
 RECT 0 583.17 48.73 583.18 ;
 RECT 872.54 583.18 874.38 584.15 ;
 RECT 860.84 583.18 862.68 584.15 ;
 RECT 817.64 583.18 820.38 584.15 ;
 RECT 796.04 583.18 797.88 584.15 ;
 RECT 0 0 914.85 583.17 ;
 RECT 906.24 583.18 914.85 584.15 ;
 RECT 892.34 583.18 904.48 584.15 ;
 RECT 876.14 583.18 890.58 584.15 ;
 RECT 866.24 583.18 870.78 584.15 ;
 RECT 851.84 583.18 859.08 584.15 ;
 RECT 841.94 583.18 850.08 584.15 ;
 RECT 834.74 583.18 840.18 584.15 ;
 RECT 827.54 583.18 831.18 584.15 ;
 RECT 822.14 583.18 825.78 584.15 ;
 RECT 807.74 583.18 815.88 584.15 ;
 RECT 799.64 583.18 805.98 584.15 ;
 RECT 790.64 583.18 794.28 584.15 ;
 RECT 784.34 583.18 788.88 584.15 ;
 RECT 716.25 583.18 782.58 584.15 ;
 RECT 701.89 583.18 714.49 584.15 ;
 RECT 685.85 583.18 700.13 584.15 ;
 RECT 671.19 583.18 684.09 584.15 ;
 RECT 658.49 583.18 669.43 584.15 ;
 RECT 642.39 583.18 656.73 584.15 ;
 RECT 612.19 583.18 640.63 584.15 ;
 RECT 597.55 583.18 610.43 584.15 ;
 RECT 583.25 583.18 595.79 584.15 ;
 RECT 568.95 583.18 581.49 584.15 ;
 RECT 554.65 583.18 567.19 584.15 ;
 RECT 487.55 583.18 552.89 584.15 ;
 RECT 473.25 583.18 485.79 584.15 ;
 RECT 458.95 583.18 471.49 584.15 ;
 RECT 444.65 583.18 457.19 584.15 ;
 RECT 430.35 583.18 442.89 584.15 ;
 RECT 416.05 583.18 428.59 584.15 ;
 RECT 403.39 583.18 414.29 584.15 ;
 RECT 390.69 583.18 401.63 584.15 ;
 RECT 377.99 583.18 388.93 584.15 ;
 RECT 363.65 583.18 376.23 584.15 ;
 RECT 350.99 583.18 361.89 584.15 ;
 RECT 296.95 583.18 349.23 584.15 ;
 RECT 259.95 583.18 295.19 584.15 ;
 RECT 234.79 583.18 258.19 584.15 ;
 RECT 183.55 583.18 233.03 584.15 ;
 LAYER METAL3 ;
 RECT 0 42.28 913.88 46.64 ;
 RECT 0 46.64 914.85 46.98 ;
 RECT 0 46.98 913.88 47.22 ;
 RECT 0.97 47.22 913.88 48.98 ;
 RECT 0 48.98 913.88 53.34 ;
 RECT 0 53.34 914.85 53.68 ;
 RECT 0 53.68 913.88 53.92 ;
 RECT 0.97 53.92 913.88 55.68 ;
 RECT 0 55.68 913.88 60.04 ;
 RECT 0 60.04 914.85 60.38 ;
 RECT 0 60.38 913.88 60.62 ;
 RECT 0.97 60.62 913.88 62.38 ;
 RECT 0 62.38 913.88 66.74 ;
 RECT 0 66.74 914.85 67.08 ;
 RECT 0 67.08 913.88 67.32 ;
 RECT 0.97 67.32 913.88 69.08 ;
 RECT 0 69.08 913.88 73.44 ;
 RECT 0 73.44 914.85 73.78 ;
 RECT 0 73.78 913.88 74.02 ;
 RECT 0.97 74.02 913.88 75.78 ;
 RECT 0 75.78 913.88 80.14 ;
 RECT 0 80.14 914.85 80.48 ;
 RECT 0 80.48 913.88 80.72 ;
 RECT 0.97 80.72 913.88 82.48 ;
 RECT 0 82.48 913.88 86.84 ;
 RECT 0 86.84 914.85 87.18 ;
 RECT 0 87.18 913.88 87.42 ;
 RECT 0.97 87.42 913.88 89.18 ;
 RECT 0 89.18 913.88 93.54 ;
 RECT 0 93.54 914.85 93.88 ;
 RECT 0 93.88 913.88 94.12 ;
 RECT 0.97 94.12 913.88 95.88 ;
 RECT 0 95.88 913.88 100.24 ;
 RECT 0 100.24 914.85 100.58 ;
 RECT 0 100.58 913.88 100.82 ;
 RECT 0.97 100.82 913.88 102.58 ;
 RECT 0 102.58 913.88 106.94 ;
 RECT 0 106.94 914.85 107.28 ;
 RECT 0 107.28 913.88 107.52 ;
 RECT 0.97 107.52 913.88 109.28 ;
 RECT 0 109.28 913.88 113.64 ;
 RECT 0 113.64 914.85 113.98 ;
 RECT 0 113.98 913.88 114.22 ;
 RECT 0.97 114.22 913.88 115.98 ;
 RECT 0 115.98 913.88 120.34 ;
 RECT 0 120.34 914.85 120.68 ;
 RECT 0 120.68 913.88 120.92 ;
 RECT 0.97 120.92 913.88 122.68 ;
 RECT 0 122.68 913.88 127.04 ;
 RECT 0 127.04 914.85 127.38 ;
 RECT 0 127.38 913.88 127.62 ;
 RECT 0.97 127.62 913.88 129.38 ;
 RECT 0 129.38 913.88 133.74 ;
 RECT 0 133.74 914.85 134.08 ;
 RECT 0 134.08 913.88 134.32 ;
 RECT 0.97 134.32 913.88 136.08 ;
 RECT 0 136.08 913.88 140.44 ;
 RECT 0 140.44 914.85 140.78 ;
 RECT 0 140.78 913.88 141.02 ;
 RECT 0.97 141.02 913.88 142.78 ;
 RECT 0 142.78 913.88 147.14 ;
 RECT 0 147.14 914.85 147.48 ;
 RECT 0 147.48 913.88 147.72 ;
 RECT 0.97 147.72 913.88 149.48 ;
 RECT 0 149.48 913.88 153.84 ;
 RECT 0 153.84 914.85 154.18 ;
 RECT 0 154.18 913.88 154.42 ;
 RECT 0.97 154.42 913.88 156.18 ;
 RECT 0 156.18 913.88 160.54 ;
 RECT 0 160.54 914.85 160.88 ;
 RECT 0 160.88 913.88 161.12 ;
 RECT 0.97 161.12 913.88 162.88 ;
 RECT 0 162.88 913.88 167.24 ;
 RECT 0 167.24 914.85 167.58 ;
 RECT 0 167.58 913.88 167.82 ;
 RECT 0.97 167.82 913.88 169.58 ;
 RECT 0 169.58 913.88 173.94 ;
 RECT 0 173.94 914.85 174.28 ;
 RECT 0 174.28 913.88 174.52 ;
 RECT 0.97 174.52 913.88 176.28 ;
 RECT 0 176.28 913.88 180.64 ;
 RECT 0 180.64 914.85 180.98 ;
 RECT 0 180.98 913.88 181.22 ;
 RECT 0.97 181.22 913.88 182.98 ;
 RECT 0 182.98 913.88 187.34 ;
 RECT 0 187.34 914.85 187.68 ;
 RECT 0 187.68 913.88 187.92 ;
 RECT 0.97 187.92 913.88 189.68 ;
 RECT 0 189.68 913.88 194.04 ;
 RECT 0 194.04 914.85 194.38 ;
 RECT 0 194.38 913.88 194.62 ;
 RECT 0.97 194.62 913.88 196.38 ;
 RECT 0 196.38 913.88 200.74 ;
 RECT 0 200.74 914.85 201.08 ;
 RECT 0 201.08 913.88 201.32 ;
 RECT 0.97 201.32 913.88 203.08 ;
 RECT 0 203.08 913.88 207.44 ;
 RECT 0 207.44 914.85 207.78 ;
 RECT 0 207.78 913.88 208.02 ;
 RECT 0.97 208.02 913.88 209.78 ;
 RECT 0 209.78 913.88 214.14 ;
 RECT 0 214.14 914.85 214.48 ;
 RECT 0 214.48 913.88 214.72 ;
 RECT 0.97 214.72 913.88 216.48 ;
 RECT 0 216.48 913.88 220.84 ;
 RECT 0 220.84 914.85 221.18 ;
 RECT 0 221.18 913.88 221.42 ;
 RECT 0.97 221.42 913.88 222.94 ;
 RECT 0.97 222.94 913.97 223.18 ;
 RECT 0.88 223.18 913.97 233.18 ;
 RECT 913.88 443.9 914.85 444.52 ;
 RECT 913.88 446.28 914.85 446.92 ;
 RECT 913.88 458.28 914.85 467.58 ;
 RECT 904.85 480.54 914.85 494.92 ;
 RECT 913.88 496.68 914.85 498.52 ;
 RECT 913.88 500.28 914.85 504.82 ;
 RECT 913.88 506.58 914.85 508.42 ;
 RECT 904.85 510.18 914.85 526.42 ;
 RECT 913.88 528.18 914.85 534.52 ;
 RECT 913.88 536.28 914.85 543.52 ;
 RECT 913.88 545.28 914.85 555.22 ;
 RECT 913.88 556.98 914.85 558.82 ;
 RECT 913.88 560.58 914.85 566.92 ;
 RECT 913.88 568.68 914.85 570.52 ;
 RECT 0.88 574.15 913.88 574.98 ;
 RECT 0.88 574.98 913.97 584.15 ;
 RECT 0.88 371.61 914.85 381.49 ;
 RECT 0.88 232.4 914.85 431.4 ;
 RECT 0 232.4 914.85 371.61 ;
 RECT 0 441.3 913.88 574.37 ;
 RECT 0 381.49 914.85 431.4 ;
 RECT 0 431.4 913.97 441.3 ;
 RECT 0 0 914.85 1.1 ;
 RECT 0.88 1.1 913.97 7.88 ;
 RECT 0.88 7.88 913.88 8.3 ;
 RECT 0 8.3 913.88 13.14 ;
 RECT 0 13.14 914.85 13.48 ;
 RECT 0 13.48 913.88 13.72 ;
 RECT 0.97 13.72 913.88 15.48 ;
 RECT 0 15.48 913.88 19.84 ;
 RECT 0 19.84 914.85 20.18 ;
 RECT 0 20.18 913.88 20.42 ;
 RECT 0.97 20.42 913.88 22.18 ;
 RECT 0 22.18 913.88 26.54 ;
 RECT 0 26.54 914.85 26.88 ;
 RECT 0 26.88 913.88 27.12 ;
 RECT 0.97 27.12 913.88 28.88 ;
 RECT 0 28.88 913.88 33.24 ;
 RECT 0 33.24 914.85 33.58 ;
 RECT 0 33.58 913.88 33.82 ;
 RECT 0.97 33.82 913.88 35.58 ;
 RECT 0 35.58 913.88 39.94 ;
 RECT 0 39.94 914.85 40.28 ;
 RECT 0 40.28 913.88 40.52 ;
 RECT 0.97 40.52 913.88 42.28 ;
 LAYER METAL4 ;
 RECT 0 0 914.85 584.15 ;
 END
END ARM7TDMI

END LIBRARY
